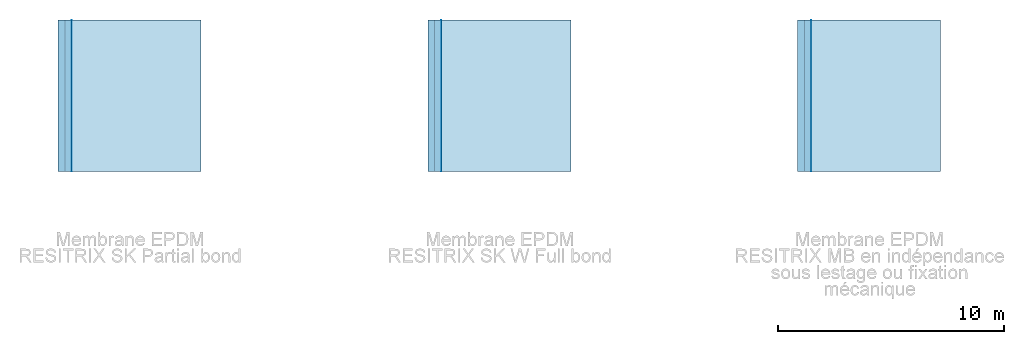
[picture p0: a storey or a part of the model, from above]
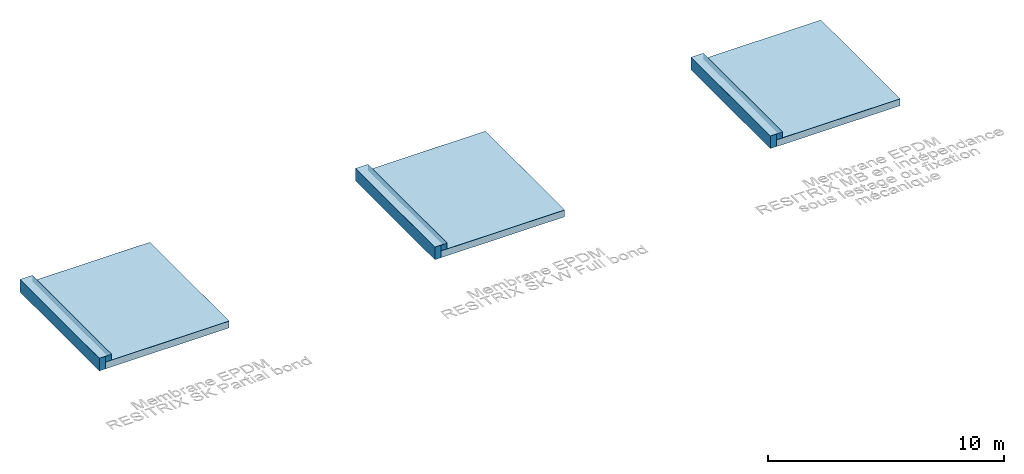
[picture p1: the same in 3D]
Properties of the parts of a building model (IFC2X3)

# File
Description: ViewDefinition [CoordinationView_V2.0]
Time: 2024-08-13T15:22:51
Written by: The EXPRESS Data Manager Version 5.02.0100.07 : 28 Aug 2013
Made in: 22.0.2.392 - Exporter 22.0.2.392 - Interface utilisateur alternative 22.0.2.392
Comment: STEP Physical File produced by: The EXPRESS Data Manager Version 5.02.0100.07 : 28 Aug 2013 * Module: EDMstepFileFactory/EDMstandAlone * Creation date: Tue Aug 13 15:22:51 2024 * Host: VM-BAG-LT-163 * Database: C:\Users\u051572\AppData\Local\Temp\944d15ae-e770-4c47-be8f-69452afcd475\728ac697-3b30-4bc3-b27e-8b7433de0d2c\ifc * Database version: 5507 * Database creation date: Tue Aug 13 15:22:50 2024 * Schema: IFC2X3 * Model: DataRepository.ifc * Model creation date: Tue Aug 13 15:22:51 2024 * Header model: DataRepository.ifc_HeaderModel * Header model creation date: Tue Aug 13 15:22:51 2024 * EDMuser: sdai-user * EDMgroup: sdai-group * License ID and type: 5605 : Permanent license. Expiry date: * EDMstepFileFactory options: 020000

# IfcSite, Default
RefLatitude: 42, 24, 53, 508911; RefLongitude: -71, -15, -29, -58837; RefElevation: 0 mm

# IfcBuilding
Pset_BuildingCommon - NumberOfStoreys: 1

# IfcBuildingStorey: Niveau:Niveau 1, Niveau 1
LongName: Niveau 1; Elevation: 0 mm

# IfcBuildingElementProxy: Texte 3D:Model Text 1 (3)
In: Niveau 1
Pset_BuildingElementProxyCommon - Reference: Model Text 1; sets with these values: 2
Name (Texte 3D:Model Text 1:...) | Shape | Width (mm) = Depth (mm) | Height (mm)
24701 | Undefined | 10 | 75.3422
24706 | Undefined | 10 | 602.738
35032

# IfcRoof: Toit de base:Lestage (à définir selon client), Toit de base:Lestage (à définir selon client):35168
In: Niveau 1
Pset_QuantityTakeOff - Reference: Lestage (à définir selon client)
Pset_RoofCommon - IsExternal: yes; Reference: Lestage (à définir selon client); ProjectedArea: 38.5877 m2; TotalArea: 38.5877 m2

# IfcRoof: Toit de base:Membrane RESITRIX MB EPDM lestée ou fixée méaniquement, Toit de base:Membrane RESITRIX MB EPDM lestée ou fixée méaniquement:35083
In: Niveau 1
Pset_QuantityTakeOff - Reference: Membrane RESITRIX MB EPDM lestée ou fixée méaniquement
Pset_RoofCommon - IsExternal: yes; Reference: Membrane RESITRIX MB EPDM lestée ou fixée méaniquement; ProjectedArea: 38.5877 m2; TotalArea: 38.5877 m2

# IfcRoof: Toit de base:Membrane RESITRIX SK EPDM Partial bond, Toit de base:Membrane RESITRIX SK EPDM Partial bond:27751
In: Niveau 1
Pset_QuantityTakeOff - Reference: Membrane RESITRIX SK EPDM Partial bond
Pset_RoofCommon - IsExternal: yes; Reference: Membrane RESITRIX SK EPDM Partial bond; ProjectedArea: 38.5877 m2; TotalArea: 38.5877 m2

# IfcRoof: Toit de base:Membrane RESITRIX SK W Full bond (4)
In: Niveau 1
Pset_QuantityTakeOff - Reference: Membrane RESITRIX SK W Full bond
Pset_RoofCommon - IsExternal: yes; Reference: Membrane RESITRIX SK W Full bond
Name (Toit de base:Membrane RESITRIX SK W Full bond:...) | ProjectedArea (m2) = TotalArea (m2)
25634 | 4.05083
35119 | 4.05083
35290 | 4.05083
35333 | 38.5877

# IfcRoof: Toit de base:Primer d’adhérence FG35 (5)
In: Niveau 1
Pset_QuantityTakeOff - Reference: Primer d’adhérence FG35
Pset_RoofCommon - Reference: Primer d’adhérence FG35; IsExternal: yes
Name (Toit de base:Primer d’adhérence FG35:...) | ProjectedArea (m2) = TotalArea (m2)
25614 | 38.5877
28714 | 4.05083
35153 | 4.05083
35273 | 38.5877
35358 | 4.05083

# IfcRoof: Toit de base:Toit 1 (3)
In: Niveau 1
Pset_QuantityTakeOff - Reference: Toit 1
Pset_RoofCommon - IsExternal: yes; Reference: Toit 1; ProjectedArea: 40.602 m2; TotalArea: 40.602 m2
Name (Toit de base:Toit 1:...)
25621
35090
35280

# IfcSlab: Toit de base:Lestage (à définir selon client), Toit de base:Lestage (à définir selon client):35168
In: Niveau 1
Type - PredefinedType: ROOF
Type - Pset_ReinforcementBarPitchOfSlab - Description: Le retridex lesté est posé en indépendance sous protection lourde : pose en indépendance sous gravier, dalles sur plots…
Type - Pset_SlabCommon - IsExternal: yes
Material: Lestage 0.8 mm
Pset_QuantityTakeOff - Reference: Lestage (à définir selon client)
Pset_ReinforcementBarPitchOfSlab - Reference: Lestage (à définir selon client)
Pset_SlabCommon - PitchAngle: 0 deg; Reference: Lestage (à définir selon client)

# IfcSlab: Toit de base:Membrane RESITRIX MB EPDM lestée ou fixée méaniquement, Toit de base:Membrane RESITRIX MB EPDM lestée ou fixée méaniquement:35083
In: Niveau 1
Type - PredefinedType: ROOF
Type - Pset_ReinforcementBarPitchOfSlab - Description: Resitrix MB offre une solution durable pour la couverture de toitures plates. La membrane de finition est composée d’une couche supérieure EPDM armée et d’une sous-couche en SBS revêtue d’un film PE.
Type - Pset_SlabCommon - IsExternal: yes
Material: Caoutchouc EPDM MB 2.1 mm, Armature en fibre de verre 1 mm
Pset_QuantityTakeOff - Reference: Membrane RESITRIX MB EPDM lestée ou fixée méaniquement
Pset_ReinforcementBarPitchOfSlab - Reference: Membrane RESITRIX MB EPDM lestée ou fixée méaniquement
Pset_SlabCommon - PitchAngle: 0 deg; Reference: Membrane RESITRIX MB EPDM lestée ou fixée méaniquement

# IfcSlab: Toit de base:Membrane RESITRIX SK EPDM Partial bond, Toit de base:Membrane RESITRIX SK EPDM Partial bond:27751
In: Niveau 1
Type - PredefinedType: ROOF
Type - Pset_ReinforcementBarPitchOfSlab - Description: Le Resitrix SK Partial Bond se compose d’une couche supérieure en caoutchouc EPDM armé et d’une sous-couche SBS partiellement autocollante revêtue par un film polyéthylène qui peut être retiré manuellement.
Type - Pset_SlabCommon - IsExternal: yes
Material: Caoutchouc EPDM SK 1.5 mm, Armature en fibre de verre 1 mm
Pset_QuantityTakeOff - Reference: Membrane RESITRIX SK EPDM Partial bond
Pset_ReinforcementBarPitchOfSlab - Reference: Membrane RESITRIX SK EPDM Partial bond
Pset_SlabCommon - PitchAngle: 0 deg; Reference: Membrane RESITRIX SK EPDM Partial bond

# IfcSlab: Toit de base:Membrane RESITRIX SK W Full bond (4)
In: Niveau 1
Type - PredefinedType: ROOF
Type - Pset_ReinforcementBarPitchOfSlab - Description: Resitrix SK W Full Bond se compose d’une couche supérieure en caoutchouc EPDM armé et d’une sous-couche autocollante en SBS. La membrane est pourvue en-dessous d’un film polyéthylène retirable manuellement.
Type - Pset_SlabCommon - IsExternal: yes
Material: Caoutchouc EPDM SK W Full bond 1.5 mm, Armature en fibre de verre 1 mm
Pset_QuantityTakeOff - Reference: Membrane RESITRIX SK W Full bond
Pset_ReinforcementBarPitchOfSlab - Reference: Membrane RESITRIX SK W Full bond
Pset_SlabCommon - PitchAngle: 0 deg; Reference: Membrane RESITRIX SK W Full bond
Name (Toit de base:Membrane RESITRIX SK W Full bond:...)
25634
35119
35290
35333

# IfcSlab: Toit de base:Primer d’adhérence FG35 (5)
In: Niveau 1
Type - PredefinedType: ROOF
Type - Pset_ReinforcementBarPitchOfSlab - Description: Le support (toiture plate) doit être préparé avec le Primer d’adhérence FG35. Le primer d’adhérence permet un collage immédiat et durable. Il faut respecter un temps de séchage de 35 minutes minimum.
Type - Pset_SlabCommon - IsExternal: yes
Material: Primer d’adhérence FG35 0.8 mm
Pset_QuantityTakeOff - Reference: Primer d’adhérence FG35
Pset_ReinforcementBarPitchOfSlab - Reference: Primer d’adhérence FG35
Pset_SlabCommon - Reference: Primer d’adhérence FG35; PitchAngle: 0 deg
Name (Toit de base:Primer d’adhérence FG35:...)
25614
28714
35153
35273
35358

# IfcSlab: Toit de base:Toit 1 (3)
In: Niveau 1
Type - PredefinedType: ROOF
Type - Pset_SlabCommon - IsExternal: yes
Material: Isolation 100 mm, Pare vapeur 0.8 mm, Béton de pente 50 mm, Structure porteuse 200 mm
Pset_QuantityTakeOff - Reference: Toit 1; sets with these values: 2
Pset_SlabCommon - PitchAngle: 0 deg; Reference: Toit 1
Name (Toit de base:Toit 1:...)
25621
35090
35280

# IfcWallStandardCase: Mur de base:Membrane RESITRIX SK W EPDM Full bond (3)
In: Niveau 1
Type - PredefinedType: STANDARD; Material: Caoutchouc EPDM SK W Full bond 1.5 mm, Armature en fibre de verre 1 mm
Type - Pset_ReinforcementBarPitchOfWall - Description: La bande d’étanchéité EPDM du relevé est réalisée avec la membrane Resitrix SK W. Elle est placée jusqu’à l’avant du mur et prolongée jusqu’à 100 mm au-delà du coin du relevé par-dessus l’isolation EPDM de la surface du toit (collée). La bande du relevé doit être collée en adhérence totale.
Type - Pset_WallCommon - IsExternal: yes
Pset_QuantityTakeOff - Reference: Membrane RESITRIX SK W EPDM Full bond
Pset_ReinforcementBarPitchOfWall - Reference: Membrane RESITRIX SK W EPDM Full bond
Pset_WallCommon - ExtendToStructure: no; LoadBearing: no; Reference: Membrane RESITRIX SK W EPDM Full bond
Name (Mur de base:Membrane RESITRIX SK W EPDM Full bond:...)
25628
35116
35287

# IfcWallStandardCase: Mur de base:Membrane RESITRIX SK W EPDM collée, Mur de base:Membrane RESITRIX SK W EPDM collée:35341
In: Niveau 1
Type - PredefinedType: STANDARD; Material: Caoutchouc EPDM SK W Full bond 1.5 mm, Armature en fibre de verre 1 mm
Type - Pset_ReinforcementBarPitchOfWall - Description: La bande d’étanchéité EPDM du relevé est réalisée avec la membrane Resitrix SK W. Elle est placée jusqu’à l’avant du mur et prolongée jusqu’à 100 mm au-delà du coin du relevé par-dessus l’isolation EPDM de la surface du toit (collée). La bande du relevé doit être collée en adhérence totale.
Type - Pset_WallCommon - IsExternal: yes
Pset_QuantityTakeOff - Reference: Membrane RESITRIX SK W EPDM collée
Pset_ReinforcementBarPitchOfWall - Reference: Membrane RESITRIX SK W EPDM collée
Pset_WallCommon - ExtendToStructure: no; LoadBearing: no; Reference: Membrane RESITRIX SK W EPDM collée

# IfcWallStandardCase: Mur de base:Mur 1 (6)
In: Niveau 1
Type - PredefinedType: STANDARD; Material: Isolation 100 mm, Maçonnerie ascendante 200 mm
Type - Pset_WallCommon - IsExternal: yes
Pset_QuantityTakeOff - Reference: Mur 1; sets with these values: 2
Pset_WallCommon - Reference: Mur 1; ExtendToStructure: no; LoadBearing: no
Name (Mur de base:Mur 1:...)
25626
25627
35095
35096
35285
35286

# IfcWallStandardCase: Mur de base:Primer d’adhérence FG35 (2)
In: Niveau 1
Type - PredefinedType: STANDARD; Material: Primer d’adhérence FG35 0.8 mm
Type - Pset_ReinforcementBarPitchOfWall - Description: Le support (toiture plate) doit être préparé avec le Primer d’adhérence FG35. Le primer d’adhérence permet un collage immédiat et durable. Il faut respecter un temps de séchage de 35 minutes minimum.
Type - Pset_WallCommon - IsExternal: yes
Pset_QuantityTakeOff - Reference: Primer d’adhérence FG35
Pset_ReinforcementBarPitchOfWall - Reference: Primer d’adhérence FG35
Pset_WallCommon - Reference: Primer d’adhérence FG35; ExtendToStructure: no; LoadBearing: no
Name (Mur de base:Primer d’adhérence FG35:...)
28479
35137
